VERSION 5.7 ;
  NOWIREEXTENSIONATPIN ON ;
  DIVIDERCHAR "/" ;
  BUSBITCHARS "[]" ;
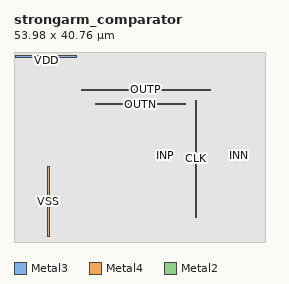
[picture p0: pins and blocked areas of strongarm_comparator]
MACRO strongarm_comparator
  CLASS BLOCK ;
  FOREIGN strongarm_comparator ;
  ORIGIN 27.100 3.940 ;
  SIZE 53.980 BY 40.760 ;
  PIN OUTN
    ANTENNAGATEAREA 6.000000 ;
    ANTENNADIFFAREA 5.840000 ;
    PORT
      LAYER Metal3 ;
        RECT -9.620 25.480 9.760 25.760 ;
    END
  END OUTN
  PIN OUTP
    ANTENNAGATEAREA 6.000000 ;
    ANTENNADIFFAREA 5.840000 ;
    PORT
      LAYER Metal3 ;
        RECT -12.680 28.540 15.140 28.820 ;
    END
  END OUTP
  PIN CLK
    ANTENNAGATEAREA 5.000000 ;
    PORT
      LAYER Metal4 ;
        RECT 11.800 1.280 12.080 26.500 ;
    END
  END CLK
  PIN INN
    ANTENNAGATEAREA 12.000000 ;
    PORT
      LAYER Metal2 ;
        RECT 21.090 14.550 21.370 14.830 ;
    END
  END INN
  PIN INP
    ANTENNAGATEAREA 12.000000 ;
    PORT
      LAYER Metal2 ;
        RECT 5.190 14.550 5.470 14.830 ;
    END
  END INP
  PIN VSS
    USE GROUND ;
    PORT
      LAYER Metal4 ;
        RECT -19.960 -2.800 -19.400 12.220 ;
    END
  END VSS
  PIN VDD
    USE POWER ;
    PORT
      LAYER Metal3 ;
        RECT -26.680 35.540 -13.700 36.100 ;
    END
  END VDD
  OBS
      LAYER Nwell ;
        RECT -23.880 0.000 23.880 33.270 ;
      LAYER Metal1 ;
        RECT -23.650 0.210 23.650 33.060 ;
      LAYER Metal2 ;
        RECT -24.010 15.130 23.650 33.060 ;
        RECT -24.010 14.250 4.890 15.130 ;
        RECT 5.770 14.250 20.790 15.130 ;
        RECT 21.670 14.250 23.650 15.130 ;
        RECT -24.010 0.210 23.650 14.250 ;
      LAYER Metal3 ;
        RECT -27.100 35.960 -26.680 36.100 ;
        RECT -27.100 35.680 -26.960 35.960 ;
        RECT -27.100 35.540 -26.680 35.680 ;
        RECT -27.100 35.240 -26.980 35.540 ;
        RECT -13.400 35.240 26.500 36.100 ;
        RECT -27.100 29.120 26.500 35.240 ;
        RECT -27.100 28.240 -12.980 29.120 ;
        RECT 15.440 28.240 26.500 29.120 ;
        RECT -27.100 26.060 26.500 28.240 ;
        RECT -27.100 25.180 -9.920 26.060 ;
        RECT 10.060 25.180 26.500 26.060 ;
        RECT -27.100 -3.220 26.500 25.180 ;
      LAYER Metal4 ;
        RECT -27.070 26.800 26.470 36.070 ;
        RECT -27.070 12.520 11.500 26.800 ;
        RECT -27.070 -3.100 -20.260 12.520 ;
        RECT -19.100 0.980 11.500 12.520 ;
        RECT 12.380 0.980 26.470 26.800 ;
        RECT -19.100 -3.100 26.470 0.980 ;
        RECT -27.070 -3.220 26.470 -3.100 ;
      LAYER Metal5 ;
        RECT -27.070 -3.940 26.880 36.820 ;
  END
END strongarm_comparator
END LIBRARY

